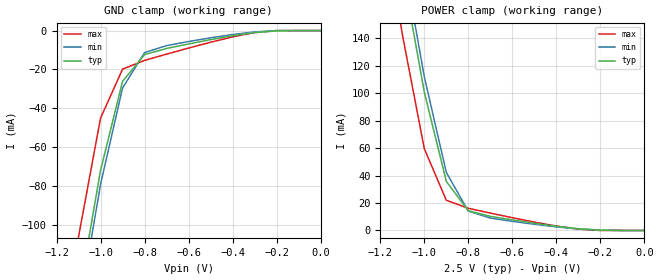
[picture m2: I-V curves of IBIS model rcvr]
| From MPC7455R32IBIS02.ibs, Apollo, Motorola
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| *   rcvr  Model   *
[Model]   rcvr
Model_type   Input
Polarity   Non-Inverting
Vinl =   0.87V
Vinh =   1.63V
|   typ   min   max
C_comp   3.119658e-12   2.857166e-12   3.290413e-12
|   typ   min   max
[Voltage range]   2.5V   2.3V   2.7V
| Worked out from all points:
|   GND clamp passes 1 mA (typ) near -0.30 V on its own axis
|   POWER clamp passes 1 mA (typ) near -0.27 V on its own axis
|   Voltage(V)   I(typ)   I(min)   I(max)
[GND_clamp]
-2.5V     -1.275A    -1.284A    -1.268A
-1.1V     -137.6mA   -145.9mA   -106.1mA
-1V       -71.92mA   -79.17mA   -45.1mA
-900mV    -26.16mA   -29.58mA   -19.86mA
-800mV    -12.36mA   -11.33mA   -15.35mA
-700mV    -9.216mA   -7.742mA   -12.12mA
-500mV    -4.675mA   -3.723mA   -6.001mA
-300mV    -1.034mA   -699.9uA   -1.019mA
-200mV    -157.7uA   0A         0A
0V        0A         0A         0A
[POWER_clamp]
-2.5V     1.716A     1.729A     1.693A
-1.2V     289mA      301.7mA    242.3mA
-1.1V     190.2mA    202.6mA    143.1mA
-1V       100.8mA    112mA      59.62mA
-900mV    35.83mA    42.3mA     22.01mA
-800mV    14.35mA    14.08mA    16.17mA
-700mV    10.31mA    9.049mA    12.67mA
-500mV    5.287mA    4.52mA     6.122mA
-300mV    1.278mA    1.06mA     962.2uA
-200mV    244.5uA    205.4uA    0A
0V        0A         0A         0A
